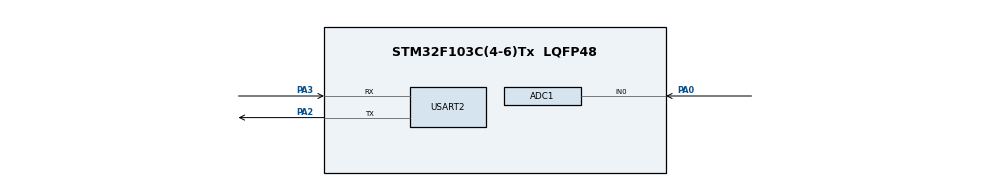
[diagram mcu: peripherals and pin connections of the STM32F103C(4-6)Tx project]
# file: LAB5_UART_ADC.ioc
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ADC1.Channel-0\#ChannelRegularConversion=ADC_CHANNEL_0
ADC1.ContinuousConvMode=ENABLE
ADC1.NbrOfConversionFlag=1
ADC1.Rank-0\#ChannelRegularConversion=1
ADC1.SamplingTime-0\#ChannelRegularConversion=ADC_SAMPLETIME_1CYCLE_5
ADC1.master=1
Mcu.Family=STM32F1
Mcu.Name=STM32F103C(4-6)Tx
Mcu.Package=LQFP48
NVIC.PriorityGroup=NVIC_PRIORITYGROUP_4
NVIC.TIM2_IRQn=true\:0\:0\:false\:false\:true\:true\:true\:true
NVIC.USART2_IRQn=true\:0\:0\:false\:false\:true\:true\:true\:true
PA0-WKUP.Signal=ADCx_IN0
PA2.Mode=Asynchronous
PA2.Signal=USART2_TX
PA3.Mode=Asynchronous
PA3.Signal=USART2_RX
ProjectManager.HeapSize=0x200
ProjectManager.StackSize=0x400
ProjectManager.TargetToolchain=STM32CubeIDE
RCC.APB1Freq_Value=8000000
RCC.APB2Freq_Value=8000000
SH.ADCx_IN0.0=ADC1_IN0,IN0
TIM2.Period=9
TIM2.Prescaler=7999
USART2.VirtualMode=VM_ASYNC
VP_TIM2_VS_ClockSourceINT.Mode=Internal
board=custom

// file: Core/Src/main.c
/* USER CODE BEGIN Header */
/**
  ******************************************************************************
  * @file           : main.c
  * @brief          : Main program body
  ******************************************************************************
  * @attention
  *
  * Copyright (c) 2023 STMicroelectronics.
  * All rights reserved.
  *
  * This software is licensed under terms that can be found in the LICENSE file
  * in the root directory of this software component.
  * If no LICENSE file comes with this software, it is provided AS-IS.
  *
  ******************************************************************************
  */
/* USER CODE END Header */
#include "main.h"
#include "fsm.h"
#include "softwaretimer.h"
#include "scheduler.h"

ADC_HandleTypeDef hadc1;

TIM_HandleTypeDef htim2;

UART_HandleTypeDef huart2;

void SystemClock_Config(void);
static void MX_GPIO_Init(void);
static void MX_ADC1_Init(void);
static void MX_USART2_UART_Init(void);
static void MX_TIM2_Init(void);

/* USER CODE BEGIN 0 */
#define MAX_BUFFER_SIZE  30
uint8_t temp = 0;
uint8_t buffer[MAX_BUFFER_SIZE];
uint8_t index_buffer = 0;
uint8_t buffer_flag = 0;
void HAL_UART_RxCpltCallback(UART_HandleTypeDef *huart){
	if(huart->Instance == USART2){

		HAL_UART_Transmit(&huart2, &temp, 1, 50);
		buffer[index_buffer++] = temp;
		if(index_buffer == 30) index_buffer = 0;

		buffer_flag = 1;
		HAL_UART_Receive_IT(&huart2, &temp, 1);
	}
}
int ADC_value;
void Led_Toggle()
{
	HAL_GPIO_TogglePin(GPIOA, GPIO_PIN_5);
}
void Uart()
{
	if(buffer_flag == 1){
			command_parser_fsm();
			buffer_flag = 0;
		}
	uart_communiation_fsm();
}
/* USER CODE END 0 */

int main(void)
{

  /* MCU Configuration--------------------------------------------------------*/

  /* Reset of all peripherals, Initializes the Flash interface and the Systick. */
  HAL_Init();

  /* Configure the system clock */
  SystemClock_Config();

  /* Initialize all configured peripherals */
  MX_GPIO_Init();
  MX_ADC1_Init();
  MX_USART2_UART_Init();
  MX_TIM2_Init();
  /* USER CODE BEGIN 2 */
  HAL_UART_Receive_IT (& huart2 , & temp , 1) ;
  HAL_TIM_Base_Start_IT(&htim2);
  char str[30];

  HAL_ADC_Start(&hadc1);
  ADC_value = HAL_ADC_GetValue(&hadc1);
  HAL_ADC_Stop(&hadc1);
  /* USER CODE END 2 */
  SCH_Add_Task(Led_Toggle, 0, 100);
  SCH_Add_Task(Uart, 0, 100);
  /* Infinite loop */
  /* USER CODE BEGIN WHILE */
	while (1){
		SCH_Dispatch_Tasks();
	}
  /* USER CODE END 3 */
}

void SystemClock_Config(void)
{
  RCC_OscInitTypeDef RCC_OscInitStruct = {0};
  RCC_ClkInitTypeDef RCC_ClkInitStruct = {0};
  RCC_PeriphCLKInitTypeDef PeriphClkInit = {0};

  /** Initializes the RCC Oscillators according to the specified parameters
  * in the RCC_OscInitTypeDef structure.
  */
  RCC_OscInitStruct.OscillatorType = RCC_OSCILLATORTYPE_HSI;
  RCC_OscInitStruct.HSIState = RCC_HSI_ON;
  RCC_OscInitStruct.HSICalibrationValue = RCC_HSICALIBRATION_DEFAULT;
  RCC_OscInitStruct.PLL.PLLState = RCC_PLL_NONE;
  if (HAL_RCC_OscConfig(&RCC_OscInitStruct) != HAL_OK)
  {
    Error_Handler();
  }

  /** Initializes the CPU, AHB and APB buses clocks
  */
  RCC_ClkInitStruct.ClockType = RCC_CLOCKTYPE_HCLK|RCC_CLOCKTYPE_SYSCLK
                              |RCC_CLOCKTYPE_PCLK1|RCC_CLOCKTYPE_PCLK2;
  RCC_ClkInitStruct.SYSCLKSource = RCC_SYSCLKSOURCE_HSI;
  RCC_ClkInitStruct.AHBCLKDivider = RCC_SYSCLK_DIV1;
  RCC_ClkInitStruct.APB1CLKDivider = RCC_HCLK_DIV1;
  RCC_ClkInitStruct.APB2CLKDivider = RCC_HCLK_DIV1;

  if (HAL_RCC_ClockConfig(&RCC_ClkInitStruct, FLASH_LATENCY_0) != HAL_OK)
  {
    Error_Handler();
  }
  PeriphClkInit.PeriphClockSelection = RCC_PERIPHCLK_ADC;
  PeriphClkInit.AdcClockSelection = RCC_ADCPCLK2_DIV2;
  if (HAL_RCCEx_PeriphCLKConfig(&PeriphClkInit) != HAL_OK)
  {
    Error_Handler();
  }
}

static void MX_ADC1_Init(void)
{

  ADC_ChannelConfTypeDef sConfig = {0};

  /** Common config
  */
  hadc1.Instance = ADC1;
  hadc1.Init.ScanConvMode = ADC_SCAN_DISABLE;
  hadc1.Init.ContinuousConvMode = ENABLE;
  hadc1.Init.DiscontinuousConvMode = DISABLE;
  hadc1.Init.ExternalTrigConv = ADC_SOFTWARE_START;
  hadc1.Init.DataAlign = ADC_DATAALIGN_RIGHT;
  hadc1.Init.NbrOfConversion = 1;
  if (HAL_ADC_Init(&hadc1) != HAL_OK)
  {
    Error_Handler();
  }

  /** Configure Regular Channel
  */
  sConfig.Channel = ADC_CHANNEL_0;
  sConfig.Rank = ADC_REGULAR_RANK_1;
  sConfig.SamplingTime = ADC_SAMPLETIME_1CYCLE_5;
  if (HAL_ADC_ConfigChannel(&hadc1, &sConfig) != HAL_OK)
  {
    Error_Handler();
  }

}

static void MX_TIM2_Init(void)
{

  TIM_ClockConfigTypeDef sClockSourceConfig = {0};
  TIM_MasterConfigTypeDef sMasterConfig = {0};

  htim2.Instance = TIM2;
  htim2.Init.Prescaler = 7999;
  htim2.Init.CounterMode = TIM_COUNTERMODE_UP;
  htim2.Init.Period = 9;
  htim2.Init.ClockDivision = TIM_CLOCKDIVISION_DIV1;
  htim2.Init.AutoReloadPreload = TIM_AUTORELOAD_PRELOAD_DISABLE;
  if (HAL_TIM_Base_Init(&htim2) != HAL_OK)
  {
    Error_Handler();
  }
  sClockSourceConfig.ClockSource = TIM_CLOCKSOURCE_INTERNAL;
  if (HAL_TIM_ConfigClockSource(&htim2, &sClockSourceConfig) != HAL_OK)
  {
    Error_Handler();
  }
  sMasterConfig.MasterOutputTrigger = TIM_TRGO_RESET;
  sMasterConfig.MasterSlaveMode = TIM_MASTERSLAVEMODE_DISABLE;
  if (HAL_TIMEx_MasterConfigSynchronization(&htim2, &sMasterConfig) != HAL_OK)
  {
    Error_Handler();
  }

}

static void MX_USART2_UART_Init(void)
{

  huart2.Instance = USART2;
  huart2.Init.BaudRate = 9600;
  huart2.Init.WordLength = UART_WORDLENGTH_8B;
  huart2.Init.StopBits = UART_STOPBITS_1;
  huart2.Init.Parity = UART_PARITY_NONE;
  huart2.Init.Mode = UART_MODE_TX_RX;
  huart2.Init.HwFlowCtl = UART_HWCONTROL_NONE;
  huart2.Init.OverSampling = UART_OVERSAMPLING_16;
  if (HAL_UART_Init(&huart2) != HAL_OK)
  {
    Error_Handler();
  }

}

static void MX_GPIO_Init(void)
{
  GPIO_InitTypeDef GPIO_InitStruct = {0};

  /* GPIO Ports Clock Enable */
  __HAL_RCC_GPIOA_CLK_ENABLE();

  /*Configure GPIO pin Output Level */
  HAL_GPIO_WritePin(LED_RED_GPIO_Port, LED_RED_Pin, GPIO_PIN_RESET);

  /*Configure GPIO pin : LED_RED_Pin */
  GPIO_InitStruct.Pin = LED_RED_Pin;
  GPIO_InitStruct.Mode = GPIO_MODE_OUTPUT_PP;
  GPIO_InitStruct.Pull = GPIO_NOPULL;
  GPIO_InitStruct.Speed = GPIO_SPEED_FREQ_LOW;
  HAL_GPIO_Init(LED_RED_GPIO_Port, &GPIO_InitStruct);

  /*Configure GPIO pin : PA6 */
  GPIO_InitStruct.Pin = GPIO_PIN_6;
  GPIO_InitStruct.Mode = GPIO_MODE_AF_PP;
  GPIO_InitStruct.Speed = GPIO_SPEED_FREQ_LOW;
  HAL_GPIO_Init(GPIOA, &GPIO_InitStruct);

}

/* USER CODE BEGIN 4 */
void HAL_TIM_PeriodElapsedCallback(TIM_HandleTypeDef *htim)
{
	SCH_Update();
}
/* USER CODE END 4 */

void Error_Handler(void)
{
  __disable_irq();
  while (1)
  {
  }
}
